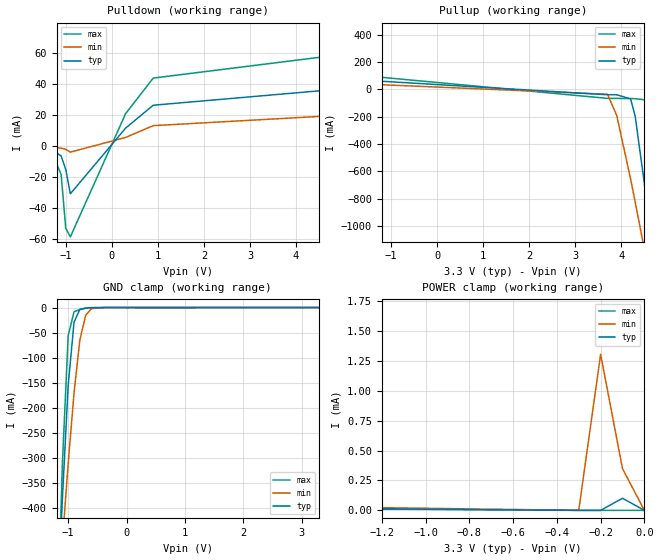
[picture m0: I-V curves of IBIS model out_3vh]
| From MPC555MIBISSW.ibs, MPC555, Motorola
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|   OUTPUT_3VH(25pf load)
[Model]   out_3vh
Model_type   Output
Polarity   Non-Inverting
|   typ   min   max
C_comp   6.7080e-13   6.0050e-13   7.6470e-13
| CAP models
| typical : model= typ
| maximum : model= wcs
| minimum : model= bcs
[Voltage range]   3.3v   3.0v   3.6v
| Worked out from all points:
|   slope of the pulldown table from 0 to 0.495 V, typ, clamps not added: 28.5 ohm
|   slope of the pullup table from 0 to 0.495 V, typ, clamps not added: 31.5 ohm
|   GND clamp passes 1 mA (typ) near -0.70 V on its own axis
|   POWER clamp passes 1 mA (typ) near -2.50 V on its own axis
|  typical: model = typ,  temp = 25,  vdd = 3.3
|  maximum: model = bcs,  temp = -40, vdd = 3.6
|  minimum: model = wcs,  temp = 150, vdd = 3.0
[Pulldown]
|  Voltage   I(typ)   I(min)   I(max)
-3.3V     -460uA     -170uA     -800uA
-1.3V     -2.637mA   -876uA     -4.81mA
-1.1V     -6.609mA   -1.542mA   -18.52mA
-1V       -15.29mA   -2.337mA   -53.3mA
-900mV    -31.07mA   -4.143mA   -58.92mA
300mV     11.41mA    5.395mA    20.77mA
900mV     26.21mA    13mA       43.77mA
5.6V      38.36mA    20.78mA    61.26mA
5.8V      40.39mA    44.54mA    64.04mA
5.9V      51.24mA    70.81mA    66.1mA
6V        84.84mA    100.7mA    84.87mA
6.6V      374.6mA    300.6mA    461.5mA
[GND_clamp]
-3.3V     -6.942A    -4.403A    -10.42A
-1.2V     -648.1mA   -632.8mA   -705.4mA
-1.1V     -383mA     -468.1mA   -313.1mA
-1V       -154.9mA   -311.4mA   -56.14mA
-900mV    -29.19mA   -170.4mA   -8.377mA
-800mV    -3.643mA   -64.63mA   -3.772mA
-700mV    -1.021mA   -15.21mA   -1.258mA
-600mV    -239.5uA   -2.066mA   -170.3uA
-400mV    -1.896uA   -47.44uA   -129.1nA
3.3V      52.74pA    15.4nA     1.967nA
[Pullup]
-3.3V     445.3mA    418.9mA    421.6mA
-2.9V     238mA      274.4mA    170.9mA
-2.5V     93.37mA    135.8mA    136.2mA
-2V       75.19mA    45.09mA    112.8mA
3.7V      -39.57mA   -36.11mA   -66.04mA
3.9V      -40.03mA   -191.4mA   -66.44mA
4.2V      -69.42mA   -653.9mA   -67.19mA
4.3V      -195.3mA   -823.4mA   -68.47mA
4.5V      -688.6mA   -1.17A     -76.02mA
4.6V      -968.5mA   -1.347A    -124.3mA
4.9V      -1.843A    -1.881A    -1.203A
6.6V      -6.988A    -4.976A    -9.093A
[POWER_clamp]
-3.3V     326.4mA    252.4mA    344.4mA
-2.9V     131.9mA    17.75mA    208.9mA
-2.7V     43.4mA     113.1uA    142.8mA
-2.6V     10.66mA    99.3uA     110.6mA
-2.4V     64.47uA    81.32uA    49.87mA
-2.2V     36.14uA    64.17uA    6.272mA
-2V       27.04uA    47.68uA    93.46uA
-1.9V     22.74uA    39.53uA    18.75uA
-300mV    62.04pA    51.07nA    15.43nA
-200mV    65.85pA    1.303mA    15.55nA
-100mV    101uA      348.4uA    16.09nA
0V        45.46pA    40.86pA    12.46nA
| RAMP models
| typical dv/dt : model=typ, temp=25
| maximum dv/dt : model=bcs, temp=-40
| minimum dv/dt : model=wcs, temp=150
|		 typ   min   max
[Ramp]
dV/dt_r	 1.03621/3.81517E-10   0.594491/3.63691E-10   2.22242/2.47557E-10
dV/dt_f  1.03621/5.74601E-10   0.594491/6.78133E-10   2.22242/2.39081E-10
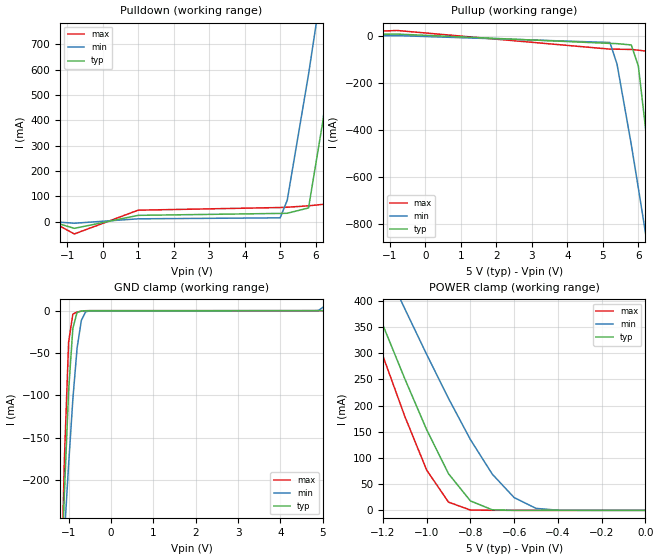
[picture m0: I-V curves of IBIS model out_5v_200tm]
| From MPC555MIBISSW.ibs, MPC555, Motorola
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| OUTPUT_5v_200tm(200ns slew rate & operating in fast [test] mode)
[Model]   out_5v_200tm
Model_type   Output
Polarity   Non-Inverting
|   typ   min   max
C_comp   5.4970e-13   4.9100e-13   6.2770e-13
| CAP models
| typical : model= typ
| maximum : model= wcs
| minimum : model= bcs
[Voltage range]   5.0v   4.5v   5.5v
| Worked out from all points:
|   slope of the pulldown table from 0 to 0.75 V, typ, clamps not added: 36.8 ohm
|   slope of the pullup table from 0 to 0.75 V, typ, clamps not added: 64.3 ohm
|   GND clamp passes 1 mA (typ) near -0.74 V on its own axis
|   POWER clamp passes 1 mA (typ) near -0.69 V on its own axis
|  typical: model = typ,  temp = 25,  vdd = 5.0
|  maximum: model = bcs,  temp = -40, vdd = 5.5
|  minimum: model = wcs,  temp = 150, vdd = 4.5
[Pulldown]
|  Voltage   I(typ)   I(min)   I(max)
-5V       -240uA     -80uA      -490uA
-1.4V     -1.679mA   -560uA     -3.107mA
-800mV    -26.75mA   -6.541mA   -48.84mA
1V        24.56mA    10.89mA    44.97mA
5V        32.25mA    14.78mA    55.47mA
5.2V      32.85mA    84.21mA    56.67mA
5.8V      53.76mA    581.1mA    62.16mA
6.2V      392.7mA    951.3mA    67.83mA
6.4V      606.4mA    1.139A     86.87mA
6.8V      1.046A     1.517A     494.6mA
7.2V      1.492A     1.899A     1A
10V       4.688A     4.599A     4.7A
[GND_clamp]
-5V       -6.334A    -4.03A     -9.36A
-1.2V     -354.9mA   -354mA     -376.6mA
-1.1V     -215.9mA   -265.7mA   -175.7mA
-1V       -94.26mA   -181.2mA   -36.97mA
-900mV    -20.69mA   -104.3mA   -4.015mA
-800mV    -2.02mA    -44.01mA   -1.604mA
-700mV    -441.8uA   -11.54mA   -531.8uA
-600mV    -101.1uA   -1.48mA    -71.66uA
-500mV    -12.93uA   -156.5uA   -2.926uA
4.8V      63.3pA     19.09uA    56.07pA
4.9V      65.68pA    287.6uA    58.28pA
5V        68.4pA     3.8mA      60.49pA
[Pullup]
-5V       181uA      126uA      248uA
-800mV    7.533mA    1.076mA    22.78mA
5.2V      -32.06mA   -28.27mA   -56.34mA
5.4V      -33.01mA   -120.3mA   -56.64mA
5.8V      -38.57mA   -460.7mA   -57.77mA
6V        -127.8mA   -646.2mA   -60.73mA
6.2V      -387.8mA   -835mA     -64.82mA
6.4V      -683.8mA   -1.026A    -70.21mA
6.6V      -989.5mA   -1.218A    -235mA
6.8V      -1.3A      -1.411A    -653.3mA
7V        -1.612A    -1.604A    -1.108A
10V       -6.37A     -4.537A    -8.229A
[POWER_clamp]
-5V       4.559A     4.065A     5.11A
-1.3V     459.2mA    564.9mA    415.1mA
-1.2V     354.1mA    474.5mA    295.2mA
-1.1V     251.6mA    385.3mA    179.8mA
-1V       154.2mA    298mA      77.05mA
-900mV    70.04mA    213.8mA    15.71mA
-800mV    18.08mA    135.3mA    606.6uA
-700mV    1.079mA    69.19mA    104.9uA
-600mV    34.26uA    24.39mA    21.06uA
-500mV    2.117uA    3.8mA      1.676uA
-400mV    134.1nA    287.6uA    45.91nA
0V        68.4pA     5.56nA     71.6pA
| RAMP models
| typical dv/dt : model=typ, temp=25
| maximum dv/dt : model=bcs, temp=-40
| minimum dv/dt : model=wcs, temp=150
|		 typ   min   max
[Ramp]
dV/dt_r   1.41569/1.97946E-09   0.874166/3.756E-09   2.93937/1.49665E-09
dV/dt_f   1.41569/2.9241E-09   0.874166/5.13701E-09   2.93937/2.08228E-09
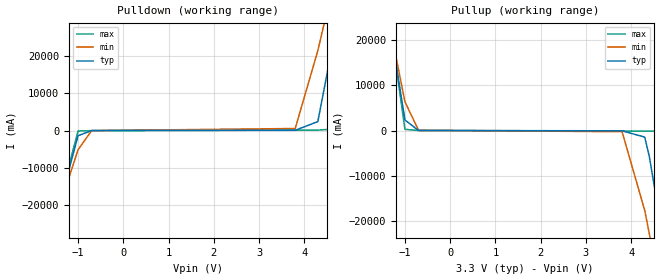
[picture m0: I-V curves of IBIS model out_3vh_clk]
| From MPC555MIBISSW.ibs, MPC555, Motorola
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| OUTPUT_3vh_clk(clk pad with 45pf load - half strength)
[Model]   out_3vh_clk
Model_type   Output
Polarity   Non-Inverting
|   typ   min   max
C_comp   5.3910e-13   4.7930e-13   6.1770e-13
| CAP models
| typical : model= typ
| maximum : model= wcs
| minimum : model= bcs
[Voltage range]   3.3v   3.0v   3.6v
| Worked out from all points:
|   slope of the pulldown table from 0 to 0.495 V, typ, clamps not added: 72.6 ohm
|   slope of the pullup table from 0 to 0.495 V, typ, clamps not added: 104 ohm
|  typical: model = typ,  temp = 25,  vdd = 3.3
|  maximum: model = bcs,  temp = -40, vdd = 3.6
|  minimum: model = wcs,  temp = 150, vdd = 3.0
[Pulldown]
|  Voltage   I(typ)   I(min)   I(max)
-3.3V     -173.6A    -120.2A    -224.6A
-1.5V     -31.57A    -27.78A    -35.88A
-1.4V     -24.48A    -22.71A    -26.9A
-1.2V     -10.44A    -12.6A     -9.348A
-1V       -1.4A      -5.157A    -139.4mA
-700mV    -12.3mA    -25.32mA   -20.14mA
3.8V      65.99mA    544.7mA    110.1mA
4.3V      2.396A     21.48A     111.8mA
4.6V      21.33A     37.12A     367.8mA
4.7V      28.66A     42.34A     4.77A
5V        50.68A     57.99A     31.31A
6.6V      209.4A     170.9A     227.6A
[Pullup]
-3.3V     209.3A     148.5A     267.4A
-1.4V     28.6A      26.66A     31.2A
-1.3V     21.26A     21.45A     21.88A
-1V       2.332A     6.358A     265.4mA
-700mV    8.352mA    54.68mA    12.48mA
3.8V      -63.44mA   -259.9mA   -106mA
4.3V      -1.458A    -17.69A    -109.8mA
4.4V      -5.66A     -22.75A    -113.5mA
4.6V      -17.46A    -32.88A    -227.2mA
4.7V      -24.54A    -37.94A    -3.739A
5V        -45.81A    -53.14A    -27.01A
6.6V      -173.6A    -140.1A    -189.2A
| RAMP models
| typical dv/dt : model=typ, temp=25
| maximum dv/dt : model=bcs, temp=-40
| minimum dv/dt : model=wcs, temp=150
|   typ   min   max
[Ramp]
dV/dt_r   1.35781/5.24663e-10   0.915541/1.16735e-09   1.72197/2.76355e-10
dV/dt_f   1.47084/3.82305e-10   0.939017/8.27759e-10   1.84354/2.10405e-10
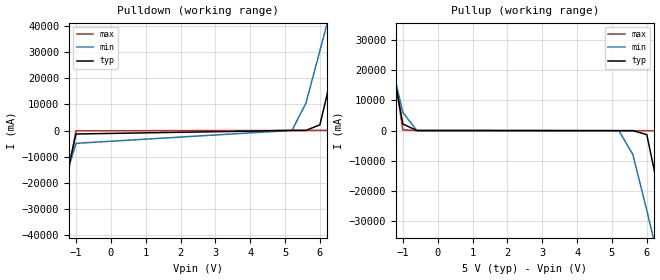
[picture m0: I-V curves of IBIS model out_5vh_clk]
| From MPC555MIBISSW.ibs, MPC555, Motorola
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| OUTPUT_5vh_clk(Half Strength)
[Model]   out_5vh_clk
Model_type   Output
Polarity   Non-Inverting
|   typ   min   max
C_comp   5.1000e-13   4.5360e-13   5.8450e-13
| CAP models
| typical : model= typ
| maximum : model= wcs
| minimum : model= bcs
[Voltage range]   5.0v   4.5v   5.5v
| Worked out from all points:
|   slope of the pulldown table from 0 to 0.75 V, typ, clamps not added: 187 ohm
|   slope of the pullup table from 0 to 0.75 V, typ, clamps not added: 744 ohm
|  typical: model = typ,  temp = 25,  vdd = 3.3,  vddh = 5.0
|  maximum: model = bcs,  temp = -40, vdd = 3.6,  vddh = 5.5
|  minimum: model = wcs,  temp = 150, vdd - 3.0,  vddh = 4.5
[Pulldown]
|  Voltage   I(typ)   I(min)   I(max)
-5V       -319.1A    -223.2A    -410.6A
-1.8V     -50.29A    -40.81A    -60.01A
-1.6V     -36.77A    -31.17A    -42.83A
-1V       -1.324A    -4.896A    -109.6mA
5.2V      33mA       62.7mA     55.14mA
5.6V      33.22mA    10.48A     55.45mA
6V        2.198A     30.5A      55.87mA
6.2V      13.35A     40.51A     56.23mA
6.4V      27.49A     50.53A     60.44mA
6.6V      41.64A     60.55A     4.454A
7V        70.6A      85.72A     39.17A
10V       376.6A     302.1A     416.9A
[Pullup]
-5V       376.6A     266A       482A
-1.6V     41.61A     35.49A     48.13A
-1.4V     27.46A     25.48A     30.08A
-1V       2.165A     5.972A     209.1mA
-600mV    981.2uA    5.173mA    1.431mA
5.2V      -38.54mA   -39.2mA    -62.68mA
5.6V      -39.06mA   -7.936A    -63.42mA
6V        -1.361A    -26.37A    -64.1mA
6.4V      -23.3A     -45.66A    -67.54mA
6.6V      -36.81A    -55.31A    -3.52A
7V        -63.86A    -74.61A    -34.31A
10V       -319.1A    -255.2A    -353.4A
| RAMP models
| typical dv/dt : model=typ, temp=25
| maximum dv/dt : model=bcs, temp=-40
| minimum dv/dt : model=wcs, temp=150
|   typ   min   max
[Ramp]
dV/dt_r  1.0664/7.1024e-10   0.614313/1.5557e-09   1.6395/4.15551e-10
dV/dt_f  0.93624/6.8968e-10   0.455091/1.2739E-09   1.4286/8.17443e-10
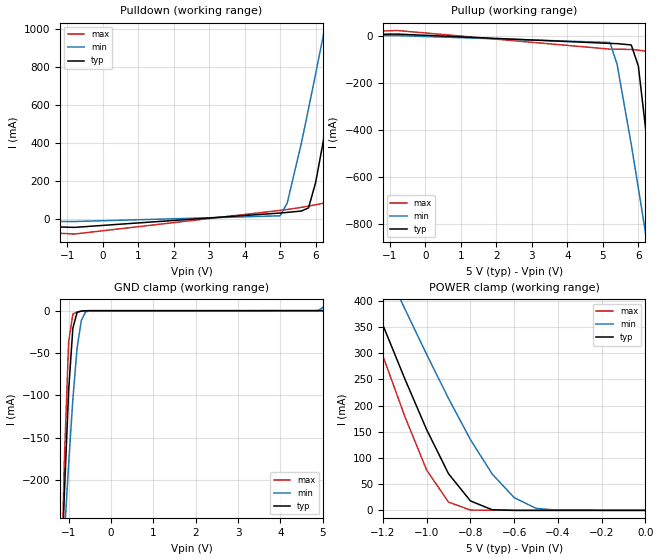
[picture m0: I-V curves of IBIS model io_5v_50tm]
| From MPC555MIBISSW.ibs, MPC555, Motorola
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| io_5v_50tm(50ns slew rate & operating in fast [test] mode)
[Model]   io_5v_50tm
Model_type   I/O
Polarity   Non-Inverting
|   typ   min   max
C_comp   5.3790e-13   4.8080e-13   6.1390e-13
| CAP models
| typical : model= typ
| maximum : model= wcs
| minimum : model= bcs
[Voltage range]   5.0v   4.5v   5.5v
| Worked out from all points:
|   slope of the pulldown table from 0 to 0.75 V, typ, clamps not added: 36.1 ohm
|   slope of the pullup table from 0 to 0.75 V, typ, clamps not added: 64.3 ohm
|   GND clamp passes 1 mA (typ) near -0.74 V on its own axis
|   POWER clamp passes 1 mA (typ) near -0.69 V on its own axis
|  typical: model = typ,  temp = 25,  vdd = 5.0
|  maximum: model = bcs,  temp = -40, vdd = 5.5
|  minimum: model = wcs,  temp = 150, vdd = 4.5
[Pulldown]
|  Voltage   I(typ)   I(min)   I(max)
-5V       -20.27mA   -7.24mA    -37.13mA
-800mV    -43.4mA    -12.37mA   -78.35mA
5V        32.25mA    17.59mA    46.18mA
5.2V      35.54mA    85.27mA    50.77mA
5.6V      42.76mA    401.3mA    62.14mA
5.8V      59.24mA    581.4mA    68.68mA
6V        192.7mA    765.2mA    75.63mA
6.2V      393.5mA    951.4mA    83mA
6.4V      607mA      1.139A     97.38mA
6.8V      1.046A     1.518A     495.7mA
7.2V      1.492A     1.899A     1.001A
10V       4.688A     4.6A       4.7A
[GND_clamp]
-5V       -6.334A    -4.03A     -9.36A
-1.2V     -354.9mA   -354mA     -376.6mA
-1.1V     -215.9mA   -265.7mA   -175.7mA
-1V       -94.26mA   -181.2mA   -36.97mA
-900mV    -20.69mA   -104.3mA   -4.015mA
-800mV    -2.02mA    -44.01mA   -1.604mA
-700mV    -441.8uA   -11.54mA   -531.8uA
-600mV    -101.1uA   -1.48mA    -71.66uA
-500mV    -12.93uA   -156.5uA   -2.926uA
4.8V      63.3pA     19.09uA    56.07pA
4.9V      65.68pA    287.6uA    58.28pA
5V        68.4pA     3.8mA      60.49pA
[Pullup]
-5V       181uA      126uA      248uA
-800mV    7.533mA    1.076mA    22.78mA
5.2V      -32.06mA   -28.27mA   -56.34mA
5.4V      -33.01mA   -120.3mA   -56.64mA
5.8V      -38.57mA   -460.7mA   -57.77mA
6V        -127.8mA   -646.2mA   -60.73mA
6.2V      -387.8mA   -835mA     -64.82mA
6.4V      -683.8mA   -1.026A    -70.21mA
6.6V      -989.5mA   -1.218A    -235mA
6.8V      -1.3A      -1.411A    -653.3mA
7V        -1.612A    -1.604A    -1.108A
10V       -6.37A     -4.537A    -8.229A
[POWER_clamp]
-5V       4.559A     4.065A     5.11A
-1.3V     459.2mA    564.9mA    415.1mA
-1.2V     354.1mA    474.5mA    295.2mA
-1.1V     251.6mA    385.3mA    179.8mA
-1V       154.2mA    298mA      77.05mA
-900mV    70.04mA    213.8mA    15.71mA
-800mV    18.08mA    135.3mA    606.6uA
-700mV    1.079mA    69.19mA    104.9uA
-600mV    34.26uA    24.39mA    21.06uA
-500mV    2.117uA    3.8mA      1.676uA
-400mV    134.1nA    287.6uA    45.91nA
0V        68.4pA     5.56nA     71.6pA
| RAMP models
| typical dv/dt : model=typ, temp=25
| maximum dv/dt : model=bcs, temp=-40
| minimum dv/dt : model=wcs, temp=150
|		 typ   min   max
[Ramp]
dV/dt_r   1.40608/1.26304E-09   0.867937/2.45213E-09   2.92699/8.78591E-10
dV/dt_f   1.40608/1.67435E-09   0.867937/2.97971E-09   2.92699/1.18105E-09
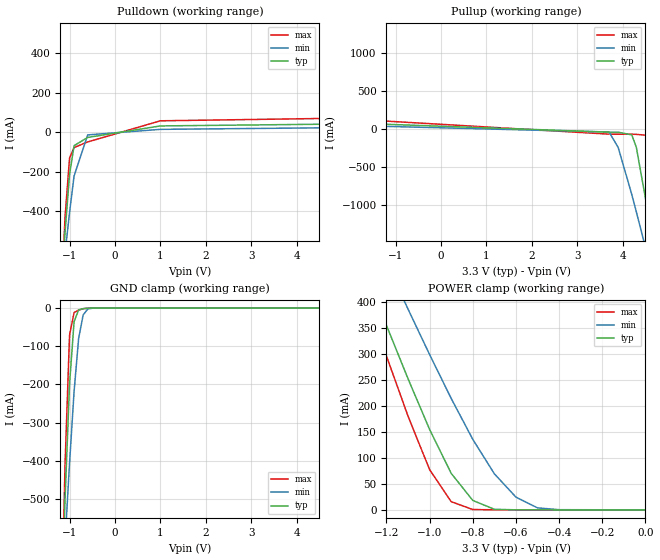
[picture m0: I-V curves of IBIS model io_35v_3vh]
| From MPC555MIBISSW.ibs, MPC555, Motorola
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| io_35v_3vh
[Model]   io_35v_3vh
Model_type   I/O
Polarity   Non-Inverting
|   typ   min   max
C_comp   7.9550e-13   7.1400e-13   9.0400e-13
| CAP models
| typical : model= typ
| maximum : model= wcs
| minimum : model= bcs
[Voltage range]   3.3v   3.0v   3.6v
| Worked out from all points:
|   slope of the pulldown table from 0 to 0.495 V, typ, clamps not added: 26.1 ohm
|   slope of the pullup table from 0 to 0.495 V, typ, clamps not added: 31.5 ohm
|   GND clamp passes 1 mA (typ) near -0.66 V on its own axis
|   POWER clamp passes 1 mA (typ) near -0.69 V on its own axis
|  typical: model = typ,  temp = 25,  vdd = 3.3
|  maximum: model = bcs,  temp = -40, vdd = 3.6
|  minimum: model = wcs,  temp = 150, vdd = 3.3
[Pulldown]
|  Voltage   I(typ)   I(min)   I(max)
-3.3V     -9.363A    -5.891A    -14.17A
-1.2V     -866.6mA   -837.5mA   -955.5mA
-1.1V     -512.5mA   -617.4mA   -436.2mA
-1V       -216.1mA   -408.8mA   -132.2mA
-900mV    -68.77mA   -222.9mA   -78.43mA
-600mV    -27.13mA   -14.28mA   -49.89mA
1V        31.24mA    13.86mA    57.19mA
5V        41.03mA    22.61mA    70.55mA
5.7V      45.72mA    494.8mA    77.62mA
5.9V      116.3mA    677.2mA    80.63mA
6.3V      509.5mA    1.05A      88.85mA
6.6V      836.4mA    1.333A     275.3mA
[GND_clamp]
-5V       -16.37A    -10.07A    -25.06A
-1.2V     -862.4mA   -836.3mA   -946.1mA
-1.1V     -505.3mA   -615.9mA   -414.3mA
-1V       -199.6mA   -406.4mA   -70.86mA
-900mV    -35.61mA   -218.7mA   -11.66mA
-800mV    -4.848mA   -79.69mA   -5.389mA
-700mV    -1.447mA   -17.89mA   -1.793mA
-600mV    -340.2uA   -2.494mA   -242uA
-500mV    -43.62uA   -353.5uA   -9.885uA
5V        119.7pA    22.38nA    107.4pA
[Pullup]
-3.3V     901.1mA    639.4mA    1.331A
-2.6V     166.2mA    83.1mA     435.7mA
-2.3V     85.86mA    51.89mA    142.7mA
3.7V      -39.57mA   -38.79mA   -66.04mA
3.9V      -40.13mA   -239.7mA   -66.44mA
4.2V      -75.72mA   -857.5mA   -67.26mA
4.3V      -239.8mA   -1.084A    -69mA
4.5V      -902.9mA   -1.549A    -79.25mA
4.6V      -1.28A     -1.786A    -138.6mA
4.7V      -1.668A    -2.023A    -482.2mA
4.9V      -2.461A    -2.502A    -1.598A
6.6V      -9.409A    -6.651A    -12.33A
[POWER_clamp]
-5V       4.559A     4.065A     5.11A
-1.3V     459.2mA    564.9mA    415.1mA
-1.2V     354.1mA    474.5mA    295.2mA
-1.1V     251.6mA    385.3mA    179.8mA
-1V       154.2mA    298mA      77.05mA
-900mV    70.04mA    213.8mA    15.71mA
-800mV    18.08mA    135.3mA    606.6uA
-700mV    1.079mA    69.19mA    104.9uA
-600mV    34.26uA    24.39mA    21.06uA
-500mV    2.117uA    3.8mA      1.676uA
-400mV    134.1nA    287.6uA    45.96nA
0V        119.7pA    21.86nA    118.6pA
| RAMP models
| typical dv/dt : model=typ, temp=25
| maximum dv/dt : model=bcs, temp=-40
| minimum dv/dt : model=wcs, temp=150
|		 typ   min   max
[Ramp]
dV/dt_r   1.1066/4.13994E-10   0.539455/4.55341E-10   2.20734/3.16899E-10
dV/dt_f   1.1066/5.05057E-10   0.539455/4.9902E-10   2.20734/2.97241E-10
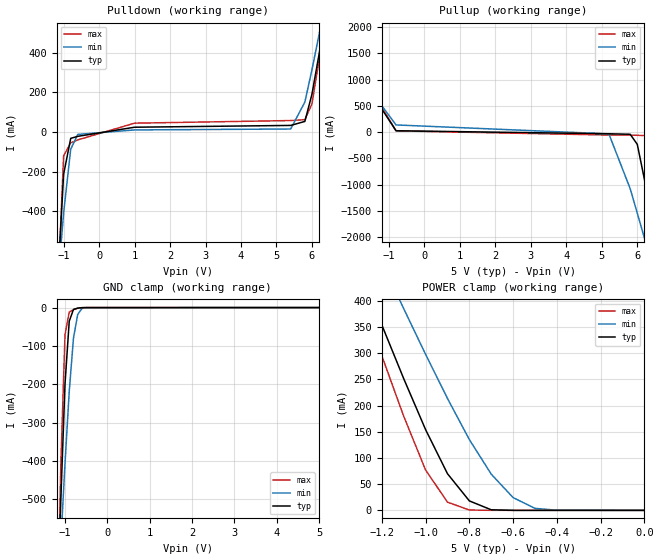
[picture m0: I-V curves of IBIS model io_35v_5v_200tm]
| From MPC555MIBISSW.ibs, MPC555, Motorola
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| io_35v_5v_200tm (fast [test] mode)
[Model]   io_35v_5v_200tm
Model_type   I/O
Polarity   Non-Inverting
|   typ   min   max
C_comp   7.9550e-13   7.1400e-13   9.0400e-13
| CAP models
| typical : model= typ
| maximum : model= wcs
| minimum : model= bcs
[Voltage range]   5.0v   4.5v   5.5v
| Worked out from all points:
|   slope of the pulldown table from 0 to 0.75 V, typ, clamps not added: 36.8 ohm
|   slope of the pullup table from 0 to 0.75 V, typ, clamps not added: 64.3 ohm
|   GND clamp passes 1 mA (typ) near -0.66 V on its own axis
|   POWER clamp passes 1 mA (typ) near -0.69 V on its own axis
|  typical: model = typ,  temp = 25,  vdd = 5.0
|  maximum: model = bcs,  temp = -40, vdd = 5.5
|  minimum: model = wcs,  temp = 150, vdd = 4.5
[Pulldown]
|  Voltage   I(typ)   I(min)   I(max)
-5V       -16.37A    -10.07A    -25.06A
-1.2V     -865.7mA   -837.2mA   -953.5mA
-1V       -212.5mA   -408.3mA   -119.1mA
-800mV    -31.59mA   -86.23mA   -54.23mA
-600mV    -21.4mA    -11.76mA   -39.28mA
1V        24.56mA    10.89mA    44.97mA
5.4V      33.61mA    15.62mA    58.17mA
5.8V      53.76mA    151.5mA    62.77mA
6V        191.2mA    314.8mA    141.8mA
6.2V      392.7mA    491.9mA    362.9mA
6.4V      606.4mA    674.5mA    608.4mA
10V       4.688A     4.123A     5.338A
[GND_clamp]
-5V       -16.37A    -10.07A    -25.06A
-1.2V     -862.4mA   -836.3mA   -946.1mA
-1.1V     -505.3mA   -615.9mA   -414.3mA
-1V       -199.6mA   -406.4mA   -70.86mA
-900mV    -35.61mA   -218.7mA   -11.66mA
-800mV    -4.848mA   -79.69mA   -5.389mA
-700mV    -1.447mA   -17.89mA   -1.793mA
-600mV    -340.2uA   -2.494mA   -242uA
-500mV    -43.62uA   -353.5uA   -9.885uA
5V        119.7pA    22.38nA    107.4pA
[Pullup]
-5V       4.559A     4.065A     5.11A
-2.6V     1.885A     1.781A     2.05A
-800mV    25.61mA    136.4mA    23.39mA
5.2V      -32.06mA   -34.63mA   -56.34mA
5.8V      -41.4mA    -1.079A    -57.77mA
6V        -233.1mA   -1.544A    -60.74mA
6.2V      -895.4mA   -2.018A    -66.08mA
6.4V      -1.661A    -2.497A    -77.86mA
6.6V      -2.453A    -2.979A    -473.6mA
6.8V      -3.258A    -3.464A    -1.588A
7V        -4.069A    -3.95A     -2.808A
10V       -16.41A    -11.32A    -21.92A
[POWER_clamp]
-5V       4.559A     4.065A     5.11A
-1.3V     459.2mA    564.9mA    415.1mA
-1.2V     354.1mA    474.5mA    295.2mA
-1.1V     251.6mA    385.3mA    179.8mA
-1V       154.2mA    298mA      77.05mA
-900mV    70.04mA    213.8mA    15.71mA
-800mV    18.08mA    135.3mA    606.6uA
-700mV    1.079mA    69.19mA    104.9uA
-600mV    34.26uA    24.39mA    21.06uA
-500mV    2.117uA    3.8mA      1.676uA
-400mV    134.1nA    287.6uA    45.96nA
0V        119.7pA    21.86nA    118.6pA
| RAMP models
| typical dv/dt : model=typ, temp=25
| maximum dv/dt : model=bcs, temp=-40
| minimum dv/dt : model=wcs, temp=150
|		 typ   min   max
[Ramp]
dV/dt_r   0.867573/5.96441E-09   0.658325/6.93233E-09   2.63476/1.55101E-09
dV/dt_f   0.867573/4.29154E-09   0.658325/6.61612E-09   2.63476/2.67291E-09
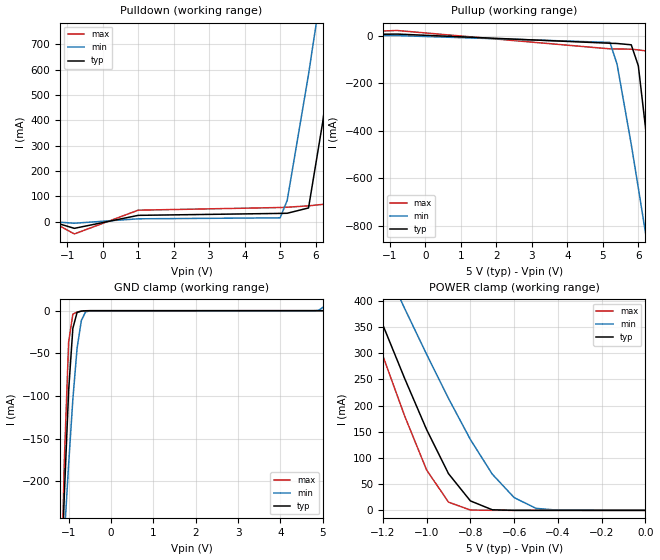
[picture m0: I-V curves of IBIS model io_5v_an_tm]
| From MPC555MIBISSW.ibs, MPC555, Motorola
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| io_5v_an_tm (5v ANALOG PAD operating in fast [test] mode)
[Model]   io_5v_an_tm
Model_type   I/O
Polarity   Non-Inverting
|   typ   min   max
C_comp   4.7270e-13   4.1940e-13   5.4410e-13
| CAP models
| typical : model= typ
| maximum : model= wcs
| minimum : model= bcs
[Voltage range]   5.0v   4.5v   5.5v
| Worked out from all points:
|   slope of the pulldown table from 0 to 0.75 V, typ, clamps not added: 36.8 ohm
|   slope of the pullup table from 0 to 0.75 V, typ, clamps not added: 65.2 ohm
|   GND clamp passes 1 mA (typ) near -0.74 V on its own axis
|   POWER clamp passes 1 mA (typ) near -0.69 V on its own axis
|  typical: model = typ,  temp = 25,  vdd = 5.0
|  maximum: model = bcs,  temp = -40, vdd = 5.5
|  minimum: model = wcs,  temp = 150, vdd = 4.5
[Pulldown]
|  Voltage   I(typ)   I(min)   I(max)
-5V       -240uA     -80uA      -490uA
-1.4V     -1.679mA   -560uA     -3.107mA
-800mV    -26.75mA   -6.541mA   -48.84mA
1V        24.56mA    10.89mA    44.97mA
5V        32.25mA    14.78mA    55.47mA
5.2V      32.85mA    84.21mA    56.67mA
5.8V      53.76mA    581.1mA    62.16mA
6.2V      392.7mA    951.3mA    67.83mA
6.4V      606.4mA    1.139A     86.87mA
6.8V      1.046A     1.517A     494.6mA
7.2V      1.492A     1.899A     1A
10V       4.688A     4.599A     4.7A
[Gnd_clamp]
-5V       -6.286A    -4.003A    -9.278A
-1.2V     -352.4mA   -351.9mA   -373.6mA
-1.1V     -214.5mA   -264.1mA   -174.5mA
-1V       -93.75mA   -180.2mA   -36.84mA
-900mV    -20.64mA   -103.8mA   -4.008mA
-800mV    -2.016mA   -43.86mA   -1.601mA
-700mV    -441uA     -11.51mA   -530.8uA
-600mV    -100.9uA   -1.477mA   -71.46uA
-500mV    -12.89uA   -156.2uA   -2.911uA
4.8V      53.73pA    19.09uA    46.07pA
4.9V      56pA       287.6uA    48.18pA
5V        58.61pA    3.8mA      50.29pA
[Pullup]
-5V       179uA      125uA      245uA
-800mV    7.443mA    1.064mA    22.53mA
5.2V      -31.27mA   -27.84mA   -54.9mA
5.4V      -32.22mA   -119.4mA   -55.19mA
5.8V      -37.77mA   -457.5mA   -56.31mA
6V        -126.5mA   -641.8mA   -59.26mA
6.2V      -384.6mA   -829.3mA   -63.34mA
6.4V      -678.2mA   -1.019A    -68.72mA
6.6V      -981.6mA   -1.209A    -232.3mA
6.8V      -1.289A    -1.401A    -647mA
7V        -1.6A      -1.593A    -1.098A
10V       -6.321A    -4.507A    -8.156A
[Power_clamp]
-5V       4.559A     4.065A     5.11A
-1.3V     459.2mA    564.9mA    415.1mA
-1.2V     354.1mA    474.5mA    295.2mA
-1.1V     251.6mA    385.3mA    179.8mA
-1V       154.2mA    298mA      77.05mA
-900mV    70.04mA    213.8mA    15.71mA
-800mV    18.08mA    135.3mA    606.6uA
-700mV    1.079mA    69.19mA    104.9uA
-600mV    34.26uA    24.39mA    21.06uA
-500mV    2.117uA    3.8mA      1.676uA
-400mV    134.1nA    287.6uA    45.9nA
0V        58.61pA    5.535nA    60.84pA
| RAMP models
| typical dv/dt : model=typ, temp=25
| maximum dv/dt : model=bcs, temp=-40
| minimum dv/dt : model=wcs, temp=150
|		 typ   min   max
[Ramp]
dV/dt_r   0.675259/6.27243E-09   0.32456/8.52644E-09   2.92974/4.99232E-09
dV/dt_f   0.675259/4.20769E-09   0.32456/4.78668E-09   2.92974/4.44386E-09
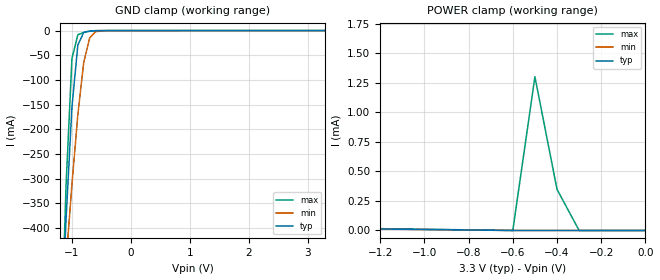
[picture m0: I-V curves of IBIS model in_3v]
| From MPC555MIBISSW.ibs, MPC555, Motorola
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| in_3v
[Model]   in_3v
Model_type   Input
Polarity   Non-Inverting
|   typ   min   max
C_comp   6.7080e-13   6.0050e-13   7.6470e-13
| CAP models
| typical : model= typ
| maximum : model= wcs
| minimum : model= bcs
[Voltage range]   3.3v   3.0v   3.6v
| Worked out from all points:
|   GND clamp passes 1 mA (typ) near -0.70 V on its own axis
|   POWER clamp passes 1 mA (typ) near -2.50 V on its own axis
|  typical: model = typ,  temp = 25,  vdd = 3.3
|  maximum: model = bcs,  temp = -40, vdd = 3.6
|  minimum: model = wcs,  temp = 150, vdd = 3.0
[GND_clamp]
|  Voltage   I(typ)   I(min)   I(max)
-3.3V     -6.942A    -4.403A    -10.42A
-1.2V     -648.2mA   -632.8mA   -705.6mA
-1.1V     -383.1mA   -468.1mA   -313.5mA
-1V       -155.1mA   -311.4mA   -56.55mA
-900mV    -29.31mA   -170.4mA   -8.438mA
-800mV    -3.656mA   -64.63mA   -3.794mA
-700mV    -1.024mA   -15.21mA   -1.263mA
-600mV    -239.7uA   -2.066mA   -170.5uA
-400mV    -1.896uA   -47.44uA   -129.1nA
3.3V      45.46pA    15.43nA    32.87pA
[POWER_clamp]
-3.3V     326.4mA    276.3mA    382.2mA
-2.7V     43.4mA     79.35mA    17.74mA
-2.6V     10.66mA    49.87mA    594.9uA
-2.5V     624uA      23.95mA    72.82uA
-2.4V     64.47uA    6.275mA    59.72uA
-2.2V     36.14uA    102.6uA    45.11uA
-2.1V     31.5uA     29.48uA    38.31uA
-600mV    71.56pA    17.96nA    51.08nA
-500mV    68.34pA    15.96nA    1.303mA
-400mV    65.19pA    15.74nA    348.4uA
-300mV    62.04pA    15.65nA    45.86pA
0V        45.46pA    15.4nA     -36.41nA
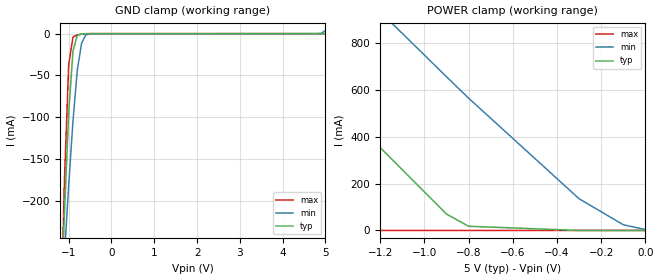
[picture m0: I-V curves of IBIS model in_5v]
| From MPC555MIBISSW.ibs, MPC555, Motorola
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| in_5v
[Model]   in_5v
Model_type   Input
Polarity   Non-Inverting
|   typ   min   max
C_comp   5.3790e-13   4.8080e-13   6.1390e-13
| CAP models
| typical : model= typ
| maximum : model= wcs
| minimum : model= bcs
[Voltage range]   5.0v   4.5v   5.5v
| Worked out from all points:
|   GND clamp passes 1 mA (typ) near -0.74 V on its own axis
|   POWER clamp passes 1 mA (typ) near -0.69 V on its own axis
|  typical: model = typ,  temp = 25,  vdd = 5.0
|  maximum: model = bcs,  temp = -40, vdd = 4.5
|  minimum: model = wcs,  temp = 150, vdd = 5.5
[GND_clamp]
|  Voltage   I(typ)   I(min)   I(max)
-5V       -6.334A    -4.03A     -9.36A
-1.2V     -354.9mA   -354mA     -376.6mA
-1.1V     -215.9mA   -265.7mA   -175.7mA
-1V       -94.26mA   -181.2mA   -36.97mA
-900mV    -20.69mA   -104.3mA   -4.015mA
-800mV    -2.02mA    -44.01mA   -1.604mA
-700mV    -441.8uA   -11.54mA   -531.8uA
-600mV    -101.1uA   -1.48mA    -71.66uA
-500mV    -12.93uA   -156.5uA   -2.926uA
4.8V      63.3pA     19.09uA    56.07pA
4.9V      65.68pA    287.6uA    58.28pA
5V        68.4pA     3.8mA      60.49pA
[POWER_clamp]
-5V       4.559A     4.541A     4.472A
-2.3V     1.552A     1.971A     1.036A
-2.2V     1.441A     1.876A     910.4mA
-1.8V     1.001A     1.497A     415.1mA
-1.5V     673.7mA    1.215A     77.05mA
-1.3V     459.2mA    1.027A     606.6uA
-1.2V     354.1mA    933.8mA    104.9uA
-900mV    70.04mA    656.3mA    45.91nA
-800mV    18.08mA    564.9mA    955.9pA
-300mV    7.23nA     135.3mA    67.14pA
-100mV    84.09pA    24.39mA    62.71pA
0V        68.4pA     3.8mA      60.49pA
